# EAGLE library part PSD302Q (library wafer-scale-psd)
WAFER SCALE INTEGRATION

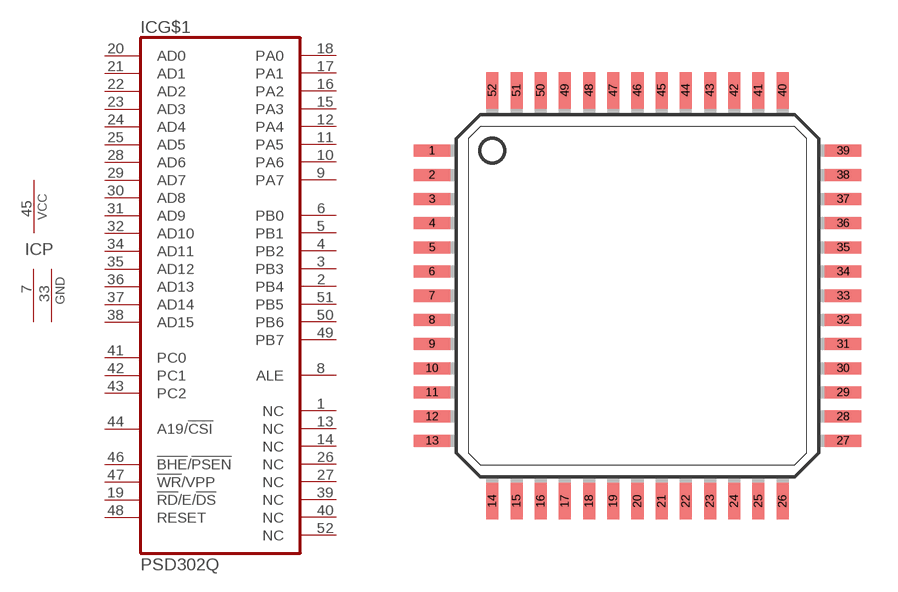
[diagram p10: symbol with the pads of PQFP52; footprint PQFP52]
Designator prefix IC; gates G$1=PSD302Q P=1VCC2GND

## PSD302Q (OC_FARNELL: unknown; OC_NEWARK: unknown)  [PQFP52]
1  G$1:NC  nc
2  G$1:PB4  out
3  G$1:PB3  out
4  G$1:PB2  out
5  G$1:PB1  out
6  G$1:PB0  out
7  P:GND  pwr
8  G$1:ALE  out
9  G$1:PA7
10  G$1:PA6
11  G$1:PA5
12  G$1:PA4
13  G$1:NC  nc
14  G$1:NC  nc
15  G$1:PA3
16  G$1:PA2
17  G$1:PA1
18  G$1:PA0
19  G$1:!RD!/E/!DS  in
20  G$1:AD0  in
21  G$1:AD1  in
22  G$1:AD2  in
23  G$1:AD3  in
24  G$1:AD4  in
25  G$1:AD5  in
26  G$1:NC  nc
27  G$1:NC  nc
28  G$1:AD6  in
29  G$1:AD7  in
30  G$1:AD8  in
31  G$1:AD9  in
32  G$1:AD10  in
33  P:GND  pwr
34  G$1:AD11  in
35  G$1:AD12  in
36  G$1:AD13  in
37  G$1:AD14  in
38  G$1:AD15  in
39  G$1:NC  nc
40  G$1:NC  nc
41  G$1:PC0  in
42  G$1:PC1  in
43  G$1:PC2  in
44  G$1:A19/!CSI  in
45  P:VCC  pwr
46  G$1:!BHE!/!PSEN  in
47  G$1:!WR!/VPP  in
48  G$1:RESET  in
49  G$1:PB7  out
50  G$1:PB6  out
51  G$1:PB5  out
52  G$1:NC  nc

## Footprint PQFP52 (pad centres in mm)
Plasic Quad Flat Package
smd 1.5 x 0.5: 1 -8.5,6; 2 -8.5,5; 3 -8.5,4; 4 -8.5,3; 5 -8.5,2; 6 -8.5,1; 7 -8.5,0; 8 -8.5,-1; 9 -8.5,-2; 10 -8.5,-3; 11 -8.5,-4; 12 -8.5,-5; 13 -8.5,-6; 27 8.5,-6; 28 8.5,-5; 29 8.5,-4; 30 8.5,-3; 31 8.5,-2; 32 8.5,-1; 33 8.5,0; 34 8.5,1; 35 8.5,2; 36 8.5,3; 37 8.5,4; 38 8.5,5; 39 8.5,6
smd 0.5 x 1.5: 14 -6,-8.5; 15 -5,-8.5; 16 -4,-8.5; 17 -3,-8.5; 18 -2,-8.5; 19 -1,-8.5; 20 0,-8.5; 21 1,-8.5; 22 2,-8.5; 23 3,-8.5; 24 4,-8.5; 25 5,-8.5; 26 6,-8.5; 40 6,8.5; 41 5,8.5; 42 4,8.5; 43 3,8.5; 44 2,8.5; 45 1,8.5; 46 0,8.5; 47 -1,8.5; 48 -2,8.5; 49 -3,8.5; 50 -4,8.5; 51 -5,8.5; 52 -6,8.5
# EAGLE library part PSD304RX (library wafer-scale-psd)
WAFER SCALE INTEGRATION

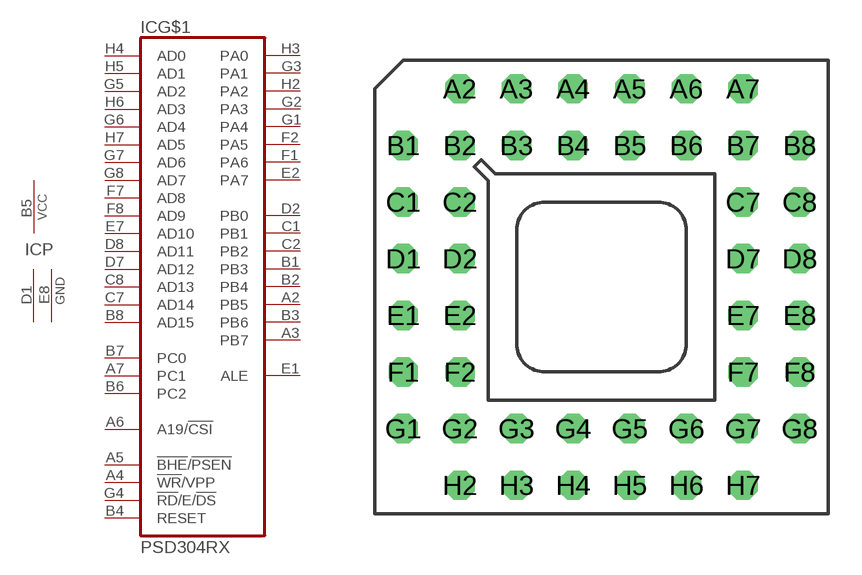
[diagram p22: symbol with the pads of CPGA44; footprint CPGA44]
Designator prefix IC; gates G$1=PSD303 P=1VCC2GND

## PSD304RX (OC_FARNELL: unknown; OC_NEWARK: unknown)  [CPGA44]
A2  G$1:PB5  out
A3  G$1:PB7  out
A4  G$1:!WR!/VPP  in
A5  G$1:!BHE!/!PSEN  in
A6  G$1:A19/!CSI  in
A7  G$1:PC1  in
B1  G$1:PB3  out
B2  G$1:PB4  out
B3  G$1:PB6  out
B4  G$1:RESET  in
B5  P:VCC  pwr
B6  G$1:PC2  in
B7  G$1:PC0  in
B8  G$1:AD15  in
C1  G$1:PB1  out
C2  G$1:PB2  out
C7  G$1:AD14  in
C8  G$1:AD13  in
D1  P:GND  pwr
D2  G$1:PB0  out
D7  G$1:AD12  in
D8  G$1:AD11  in
E1  G$1:ALE  out
E2  G$1:PA7
E7  G$1:AD10  in
E8  P:GND  pwr
F1  G$1:PA6
F2  G$1:PA5
F7  G$1:AD8  in
F8  G$1:AD9  in
G1  G$1:PA4
G2  G$1:PA3
G3  G$1:PA1
G4  G$1:!RD!/E/!DS  in
G5  G$1:AD2  in
G6  G$1:AD4  in
G7  G$1:AD6  in
G8  G$1:AD7  in
H2  G$1:PA2
H3  G$1:PA0
H4  G$1:AD0  in
H5  G$1:AD1  in
H6  G$1:AD3  in
H7  G$1:AD5  in

## Footprint CPGA44 (pad centres in mm)
Pin Grid Array
drill 0.813 octagon: A2 -6.35,8.89; A3 -3.81,8.89; A4 -1.27,8.89; A5 1.27,8.89; A6 3.81,8.89; A7 6.35,8.89; B1 -8.89,6.35; B2 -6.35,6.35; B3 -3.81,6.35; B4 -1.27,6.35; B5 1.27,6.35; B6 3.81,6.35; B7 6.35,6.35; B8 8.89,6.35; C1 -8.89,3.81; C2 -6.35,3.81; C7 6.35,3.81; C8 8.89,3.81; D1 -8.89,1.27; D2 -6.35,1.27; D7 6.35,1.27; D8 8.89,1.27; E1 -8.89,-1.27; E2 -6.35,-1.27; E7 6.35,-1.27; E8 8.89,-1.27; F1 -8.89,-3.81; F2 -6.35,-3.81; F7 6.35,-3.81; F8 8.89,-3.81; G1 -8.89,-6.35; G2 -6.35,-6.35; G3 -3.81,-6.35; G4 -1.27,-6.35; G5 1.27,-6.35; G6 3.81,-6.35; G7 6.35,-6.35; G8 8.89,-6.35; H2 -6.35,-8.89; H3 -3.81,-8.89; H4 -1.27,-8.89; H5 1.27,-8.89; H6 3.81,-8.89; H7 6.35,-8.89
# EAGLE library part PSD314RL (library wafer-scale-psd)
WAFER SCALE INTEGRATION

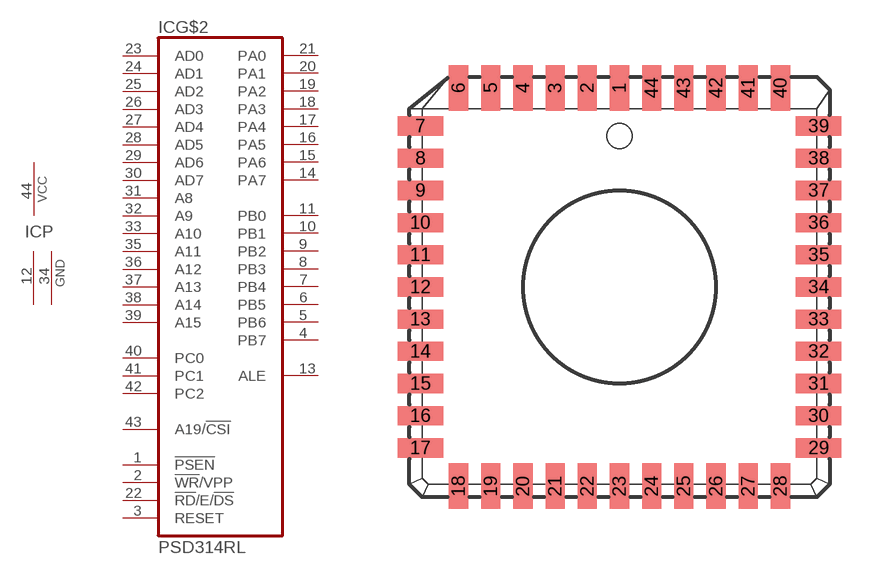
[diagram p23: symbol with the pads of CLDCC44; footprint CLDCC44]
Designator prefix IC; gates G$2=PSD312 P=1VCC2GND

## PSD314RL (OC_FARNELL: unknown; OC_NEWARK: unknown)  [CLDCC44]
1  G$2:!PSEN  in
2  G$2:!WR!/VPP  in
3  G$2:RESET  in
4  G$2:PB7  out
5  G$2:PB6  out
6  G$2:PB5  out
7  G$2:PB4  out
8  G$2:PB3  out
9  G$2:PB2  out
10  G$2:PB1  out
11  G$2:PB0  out
12  P:GND  pwr
13  G$2:ALE  out
14  G$2:PA7
15  G$2:PA6
16  G$2:PA5
17  G$2:PA4
18  G$2:PA3
19  G$2:PA2
20  G$2:PA1
21  G$2:PA0
22  G$2:!RD!/E/!DS  in
23  G$2:AD0  in
24  G$2:AD1  in
25  G$2:AD2  in
26  G$2:AD3  in
27  G$2:AD4  in
28  G$2:AD5  in
29  G$2:AD6  in
30  G$2:AD7  in
31  G$2:A8  in
32  G$2:A9  in
33  G$2:A10  in
34  P:GND  pwr
35  G$2:A11  in
36  G$2:A12  in
37  G$2:A13  in
38  G$2:A14  in
39  G$2:A15  in
40  G$2:PC0  in
41  G$2:PC1  in
42  G$2:PC2  in
43  G$2:A19/!CSI  in
44  P:VCC  pwr

## Footprint CLDCC44 (pad centres in mm)
CERAMIC LEADED CHIP CARRIER square
smd 0.76 x 1.8: 1 0,7.86; 2 -1.27,7.86; 3 -2.54,7.86; 4 -3.81,7.86; 5 -5.08,7.86; 6 -6.35,7.86; 18 -6.35,-7.86; 19 -5.08,-7.86; 20 -3.81,-7.86; 21 -2.54,-7.86; 22 -1.27,-7.86; 23 0,-7.86; 24 1.27,-7.86; 25 2.54,-7.86; 26 3.81,-7.86; 27 5.08,-7.86; 28 6.35,-7.86; 40 6.35,7.86; 41 5.08,7.86; 42 3.81,7.86; 43 2.54,7.86; 44 1.27,7.86
smd 1.8 x 0.76: 7 -7.86,6.35; 8 -7.86,5.08; 9 -7.86,3.81; 10 -7.86,2.54; 11 -7.86,1.27; 12 -7.86,0; 13 -7.86,-1.27; 14 -7.86,-2.54; 15 -7.86,-3.81; 16 -7.86,-5.08; 17 -7.86,-6.35; 29 7.86,-6.35; 30 7.86,-5.08; 31 7.86,-3.81; 32 7.86,-2.54; 33 7.86,-1.27; 34 7.86,0; 35 7.86,1.27; 36 7.86,2.54; 37 7.86,3.81; 38 7.86,5.08; 39 7.86,6.35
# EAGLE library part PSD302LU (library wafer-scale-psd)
WAFER SCALE INTEGRATION

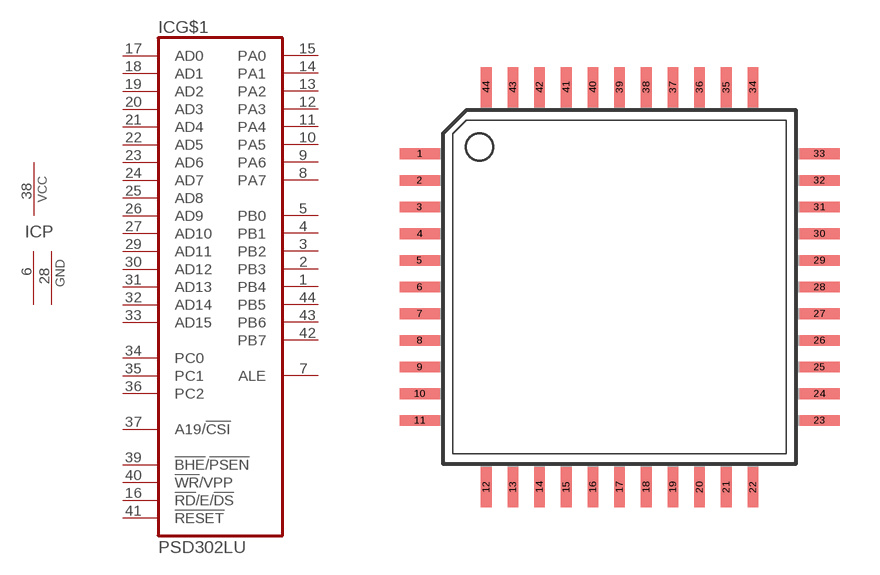
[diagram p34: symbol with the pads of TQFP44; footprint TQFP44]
Designator prefix IC; gates G$1=PSD302L P=1VCC2GND

## PSD302LU (OC_FARNELL: unknown; OC_NEWARK: unknown)  [TQFP44]
1  G$1:PB4  out
2  G$1:PB3  out
3  G$1:PB2  out
4  G$1:PB1  out
5  G$1:PB0  out
6  P:GND  pwr
7  G$1:ALE  out
8  G$1:PA7
9  G$1:PA6
10  G$1:PA5
11  G$1:PA4
12  G$1:PA3
13  G$1:PA2
14  G$1:PA1
15  G$1:PA0
16  G$1:!RD!/E/!DS  in
17  G$1:AD0  in
18  G$1:AD1  in
19  G$1:AD2  in
20  G$1:AD3  in
21  G$1:AD4  in
22  G$1:AD5  in
23  G$1:AD6  in
24  G$1:AD7  in
25  G$1:AD8  in
26  G$1:AD9  in
27  G$1:AD10  in
28  P:GND  pwr
29  G$1:AD11  in
30  G$1:AD12  in
31  G$1:AD13  in
32  G$1:AD14  in
33  G$1:AD15  in
34  G$1:PC0  in
35  G$1:PC1  in
36  G$1:PC2  in
37  G$1:A19/!CSI  in
38  P:VCC  pwr
39  G$1:!BHE!/!PSEN  in
40  G$1:!WR!/VPP  in
41  G$1:!RESET  in
42  G$1:PB7  out
43  G$1:PB6  out
44  G$1:PB5  out

## Footprint TQFP44 (pad centres in mm)
Thin Plasic Quad Flat Package 13x13mm
smd 1.5 x 0.4: 1 -7.5,5; 2 -7.5,4; 3 -7.5,3; 4 -7.5,2; 5 -7.5,1; 6 -7.5,0; 7 -7.5,-1; 8 -7.5,-2; 9 -7.5,-3; 10 -7.5,-4; 11 -7.5,-5; 23 7.5,-5; 24 7.5,-4; 25 7.5,-3; 26 7.5,-2; 27 7.5,-1; 28 7.5,0; 29 7.5,1; 30 7.5,2; 31 7.5,3; 32 7.5,4; 33 7.5,5
smd 0.4 x 1.5: 12 -5,-7.5; 13 -4,-7.5; 14 -3,-7.5; 15 -2,-7.5; 16 -1,-7.5; 17 0,-7.5; 18 1,-7.5; 19 2,-7.5; 20 3,-7.5; 21 4,-7.5; 22 5,-7.5; 34 5,7.5; 35 4,7.5; 36 3,7.5; 37 2,7.5; 38 1,7.5; 39 0,7.5; 40 -1,7.5; 41 -2,7.5; 42 -3,7.5; 43 -4,7.5; 44 -5,7.5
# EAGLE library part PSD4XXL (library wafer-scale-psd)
WAFER SCALE INTEGRATION

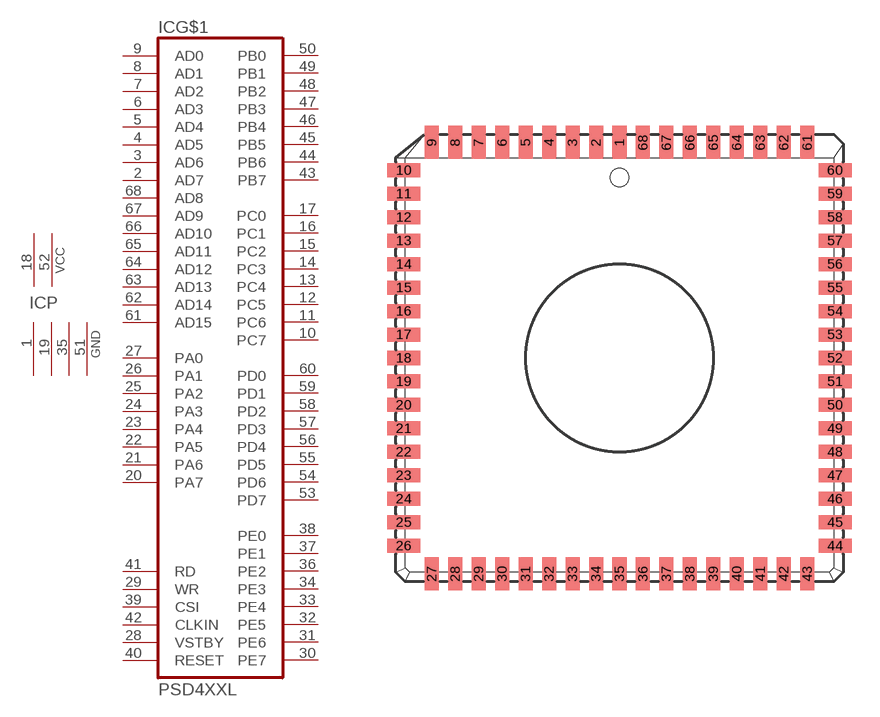
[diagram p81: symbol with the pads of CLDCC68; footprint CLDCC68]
Designator prefix IC; gates G$1=PSD4XX P=2VCC4GND

## PSD4XXL (OC_FARNELL: unknown; OC_NEWARK: unknown)  [CLDCC68]
1  P:GND  pwr
2  G$1:AD7
3  G$1:AD6
4  G$1:AD5
5  G$1:AD4
6  G$1:AD3
7  G$1:AD2
8  G$1:AD1
9  G$1:AD0
10  G$1:PC7
11  G$1:PC6
12  G$1:PC5
13  G$1:PC4
14  G$1:PC3
15  G$1:PC2
16  G$1:PC1
17  G$1:PC0
18  P:VCC  pwr
19  P:GND  pwr
20  G$1:PA7
21  G$1:PA6
22  G$1:PA5
23  G$1:PA4
24  G$1:PA3
25  G$1:PA2
26  G$1:PA1
27  G$1:PA0
28  G$1:VSTBY  in
29  G$1:WR  in
30  G$1:PE7
31  G$1:PE6
32  G$1:PE5
33  G$1:PE4
34  G$1:PE3
35  P:GND  pwr
36  G$1:PE2
37  G$1:PE1
38  G$1:PE0
39  G$1:CSI  in
40  G$1:RESET  in
41  G$1:RD  in
42  G$1:CLKIN  in
43  G$1:PB7
44  G$1:PB6
45  G$1:PB5
46  G$1:PB4
47  G$1:PB3
48  G$1:PB2
49  G$1:PB1
50  G$1:PB0
51  P:GND  pwr
52  P:VCC  pwr
53  G$1:PD7
54  G$1:PD6
55  G$1:PD5
56  G$1:PD4
57  G$1:PD3
58  G$1:PD2
59  G$1:PD1
60  G$1:PD0
61  G$1:AD15
62  G$1:AD14
63  G$1:AD13
64  G$1:AD12
65  G$1:AD11
66  G$1:AD10
67  G$1:AD9
68  G$1:AD8

## Footprint CLDCC68 (pad centres in mm)
CERAMIC LEADED CHIP CARRIER square
smd 0.76 x 1.8: 1 0,11.67; 2 -1.27,11.67; 3 -2.54,11.67; 4 -3.81,11.67; 5 -5.08,11.67; 6 -6.35,11.67; 7 -7.62,11.67; 8 -8.89,11.67; 9 -10.16,11.67; 27 -10.16,-11.67; 28 -8.89,-11.67; 29 -7.62,-11.67; 30 -6.35,-11.67; 31 -5.08,-11.67; 32 -3.81,-11.67; 33 -2.54,-11.67; 34 -1.27,-11.67; 35 0,-11.67; 36 1.27,-11.67; 37 2.54,-11.67; 38 3.81,-11.67; 39 5.08,-11.67; 40 6.35,-11.67; 41 7.62,-11.67; 42 8.89,-11.67; 43 10.16,-11.67; 61 10.16,11.67; 62 8.89,11.67; 63 7.62,11.67; 64 6.35,11.67; 65 5.08,11.67; 66 3.81,11.67; 67 2.54,11.67; 68 1.27,11.67
smd 1.8 x 0.76: 10 -11.67,10.16; 11 -11.67,8.89; 12 -11.67,7.62; 13 -11.67,6.35; 14 -11.67,5.08; 15 -11.67,3.81; 16 -11.67,2.54; 17 -11.67,1.27; 18 -11.67,0; 19 -11.67,-1.27; 20 -11.67,-2.54; 21 -11.67,-3.81; 22 -11.67,-5.08; 23 -11.67,-6.35; 24 -11.67,-7.62; 25 -11.67,-8.89; 26 -11.67,-10.16; 44 11.67,-10.16; 45 11.67,-8.89; 46 11.67,-7.62; 47 11.67,-6.35; 48 11.67,-5.08; 49 11.67,-3.81; 50 11.67,-2.54; 51 11.67,-1.27; 52 11.67,0; 53 11.67,1.27; 54 11.67,2.54; 55 11.67,3.81; 56 11.67,5.08; 57 11.67,6.35; 58 11.67,7.62; 59 11.67,8.89; 60 11.67,10.16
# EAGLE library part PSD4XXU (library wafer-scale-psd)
WAFER SCALE INTEGRATION

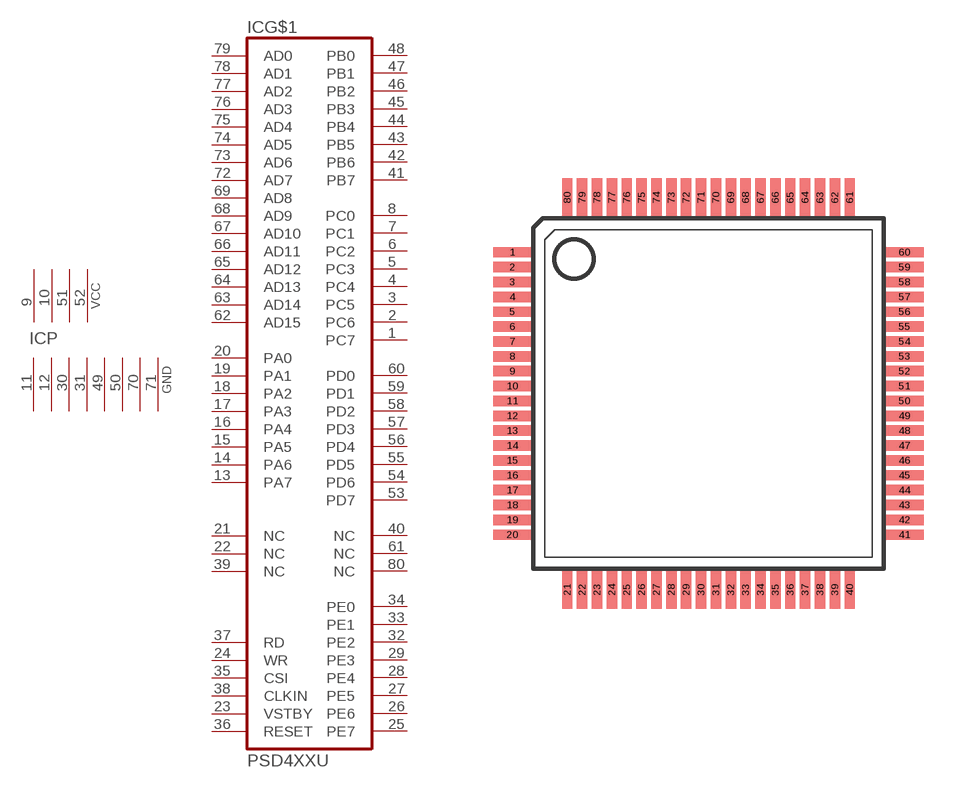
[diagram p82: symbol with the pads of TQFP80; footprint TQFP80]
Designator prefix IC; gates G$1=PSD4XXU P=4VCC8GND

## PSD4XXU (OC_FARNELL: unknown; OC_NEWARK: unknown)  [TQFP80]
1  G$1:PC7
2  G$1:PC6
3  G$1:PC5
4  G$1:PC4
5  G$1:PC3
6  G$1:PC2
7  G$1:PC1
8  G$1:PC0
9  P:VCC  pwr
10  P:VCC  pwr
11  P:GND  pwr
12  P:GND  pwr
13  G$1:PA7
14  G$1:PA6
15  G$1:PA5
16  G$1:PA4
17  G$1:PA3
18  G$1:PA2
19  G$1:PA1
20  G$1:PA0
21  G$1:NC  nc
22  G$1:NC  nc
23  G$1:VSTBY  in
24  G$1:WR  in
25  G$1:PE7
26  G$1:PE6
27  G$1:PE5
28  G$1:PE4
29  G$1:PE3
30  P:GND  pwr
31  P:GND  pwr
32  G$1:PE2
33  G$1:PE1
34  G$1:PE0
35  G$1:CSI  in
36  G$1:RESET  in
37  G$1:RD  in
38  G$1:CLKIN  in
39  G$1:NC  nc
40  G$1:NC  nc
41  G$1:PB7
42  G$1:PB6
43  G$1:PB5
44  G$1:PB4
45  G$1:PB3
46  G$1:PB2
47  G$1:PB1
48  G$1:PB0
49  P:GND  pwr
50  P:GND  pwr
51  P:VCC  pwr
52  P:VCC  pwr
53  G$1:PD7
54  G$1:PD6
55  G$1:PD5
56  G$1:PD4
57  G$1:PD3
58  G$1:PD2
59  G$1:PD1
60  G$1:PD0
61  G$1:NC  nc
62  G$1:AD15
63  G$1:AD14
64  G$1:AD13
65  G$1:AD12
66  G$1:AD11
67  G$1:AD10
68  G$1:AD9
69  G$1:AD8
70  P:GND  pwr
71  P:GND  pwr
72  G$1:AD7
73  G$1:AD6
74  G$1:AD5
75  G$1:AD4
76  G$1:AD3
77  G$1:AD2
78  G$1:AD1
79  G$1:AD0
80  G$1:NC  nc

## Footprint TQFP80 (pad centres in mm)
Thin Quad Flat Pack
smd 1.3 x 0.35: 1 -6.595,4.75; 2 -6.595,4.25; 3 -6.595,3.75; 4 -6.595,3.25; 5 -6.595,2.75; 6 -6.595,2.25; 7 -6.595,1.75; 8 -6.595,1.25; 9 -6.595,0.75; 10 -6.595,0.25; 11 -6.595,-0.25; 12 -6.595,-0.75; 13 -6.595,-1.25; 14 -6.595,-1.75; 15 -6.595,-2.25; 16 -6.595,-2.75; 17 -6.595,-3.25; 18 -6.595,-3.75; 19 -6.595,-4.25; 20 -6.595,-4.75; 41 6.595,-4.75; 42 6.595,-4.25; 43 6.595,-3.75; 44 6.595,-3.25; 45 6.595,-2.75; 46 6.595,-2.25; 47 6.595,-1.75; 48 6.595,-1.25; 49 6.595,-0.75; 50 6.595,-0.25; 51 6.595,0.25; 52 6.595,0.75; 53 6.595,1.25; 54 6.595,1.75; 55 6.595,2.25; 56 6.595,2.75; 57 6.595,3.25; 58 6.595,3.75; 59 6.595,4.25; 60 6.595,4.75
smd 0.35 x 1.3: 21 -4.75,-6.595; 22 -4.25,-6.595; 23 -3.75,-6.595; 24 -3.25,-6.595; 25 -2.75,-6.595; 26 -2.25,-6.595; 27 -1.75,-6.595; 28 -1.25,-6.595; 29 -0.75,-6.595; 30 -0.25,-6.595; 31 0.25,-6.595; 32 0.75,-6.595; 33 1.25,-6.595; 34 1.75,-6.595; 35 2.25,-6.595; 36 2.75,-6.595; 37 3.25,-6.595; 38 3.75,-6.595; 39 4.25,-6.595; 40 4.75,-6.595; 61 4.75,6.595; 62 4.25,6.595; 63 3.75,6.595; 64 3.25,6.595; 65 2.75,6.595; 66 2.25,6.595; 67 1.75,6.595; 68 1.25,6.595; 69 0.75,6.595; 70 0.25,6.595; 71 -0.25,6.595; 72 -0.75,6.595; 73 -1.25,6.595; 74 -1.75,6.595; 75 -2.25,6.595; 76 -2.75,6.595; 77 -3.25,6.595; 78 -3.75,6.595; 79 -4.25,6.595; 80 -4.75,6.595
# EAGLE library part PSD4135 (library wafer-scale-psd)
WAFER SCALE INTEGRATION

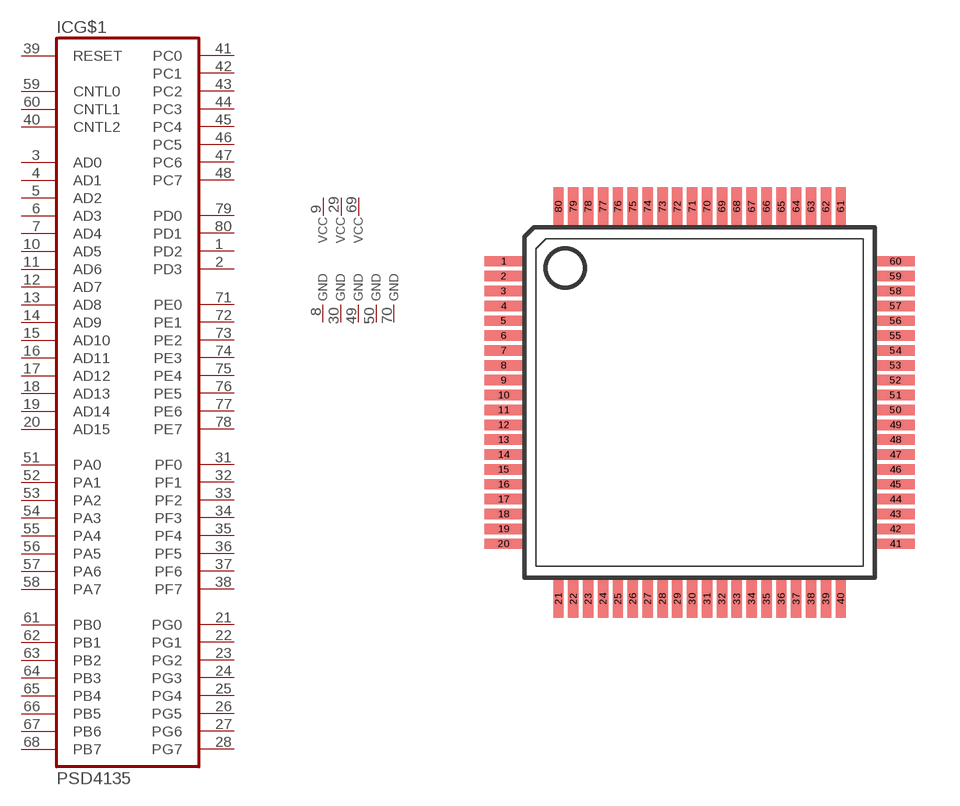
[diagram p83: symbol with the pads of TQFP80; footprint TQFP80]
Designator prefix IC; gates G$1=PSD4135 G1=GND G2=GND G3=GND G4=GND G5=GND V1=VCC V2=VCC V3=VCC

## PSD4135 (OC_FARNELL: unknown; OC_NEWARK: unknown)  [TQFP80]
1  G$1:PD2
2  G$1:PD3
3  G$1:AD0
4  G$1:AD1
5  G$1:AD2
6  G$1:AD3
7  G$1:AD4
8  G1:GNG  pwr
9  V1:VCC  pwr
10  G$1:AD5
11  G$1:AD6
12  G$1:AD7
13  G$1:AD8
14  G$1:AD9
15  G$1:AD10
16  G$1:AD11
17  G$1:AD12
18  G$1:AD13
19  G$1:AD14
20  G$1:AD15
21  G$1:PG0
22  G$1:PG1
23  G$1:PG2
24  G$1:PG3
25  G$1:PG4
26  G$1:PG5
27  G$1:PG6
28  G$1:PG7
29  V2:VCC  pwr
30  G2:GNG  pwr
31  G$1:PF0
32  G$1:PF1
33  G$1:PF2
34  G$1:PF3
35  G$1:PF4
36  G$1:PF5
37  G$1:PF6
38  G$1:PF7
39  G$1:RESET  in
40  G$1:CNTL2  in
41  G$1:PC0
42  G$1:PC1
43  G$1:PC2
44  G$1:PC3
45  G$1:PC4
46  G$1:PC5
47  G$1:PC6
48  G$1:PC7
49  G3:GNG  pwr
50  G4:GNG  pwr
51  G$1:PA0
52  G$1:PA1
53  G$1:PA2
54  G$1:PA3
55  G$1:PA4
56  G$1:PA5
57  G$1:PA6
58  G$1:PA7
59  G$1:CNTL0  in
60  G$1:CNTL1  in
61  G$1:PB0
62  G$1:PB1
63  G$1:PB2
64  G$1:PB3
65  G$1:PB4
66  G$1:PB5
67  G$1:PB6
68  G$1:PB7
69  V3:VCC  pwr
70  G5:GNG  pwr
71  G$1:PE0
72  G$1:PE1
73  G$1:PE2
74  G$1:PE3
75  G$1:PE4
76  G$1:PE5
77  G$1:PE6
78  G$1:PE7
79  G$1:PD0
80  G$1:PD1

## Footprint TQFP80 (pad centres in mm)
Thin Quad Flat Pack
smd 1.3 x 0.35: 1 -6.595,4.75; 2 -6.595,4.25; 3 -6.595,3.75; 4 -6.595,3.25; 5 -6.595,2.75; 6 -6.595,2.25; 7 -6.595,1.75; 8 -6.595,1.25; 9 -6.595,0.75; 10 -6.595,0.25; 11 -6.595,-0.25; 12 -6.595,-0.75; 13 -6.595,-1.25; 14 -6.595,-1.75; 15 -6.595,-2.25; 16 -6.595,-2.75; 17 -6.595,-3.25; 18 -6.595,-3.75; 19 -6.595,-4.25; 20 -6.595,-4.75; 41 6.595,-4.75; 42 6.595,-4.25; 43 6.595,-3.75; 44 6.595,-3.25; 45 6.595,-2.75; 46 6.595,-2.25; 47 6.595,-1.75; 48 6.595,-1.25; 49 6.595,-0.75; 50 6.595,-0.25; 51 6.595,0.25; 52 6.595,0.75; 53 6.595,1.25; 54 6.595,1.75; 55 6.595,2.25; 56 6.595,2.75; 57 6.595,3.25; 58 6.595,3.75; 59 6.595,4.25; 60 6.595,4.75
smd 0.35 x 1.3: 21 -4.75,-6.595; 22 -4.25,-6.595; 23 -3.75,-6.595; 24 -3.25,-6.595; 25 -2.75,-6.595; 26 -2.25,-6.595; 27 -1.75,-6.595; 28 -1.25,-6.595; 29 -0.75,-6.595; 30 -0.25,-6.595; 31 0.25,-6.595; 32 0.75,-6.595; 33 1.25,-6.595; 34 1.75,-6.595; 35 2.25,-6.595; 36 2.75,-6.595; 37 3.25,-6.595; 38 3.75,-6.595; 39 4.25,-6.595; 40 4.75,-6.595; 61 4.75,6.595; 62 4.25,6.595; 63 3.75,6.595; 64 3.25,6.595; 65 2.75,6.595; 66 2.25,6.595; 67 1.75,6.595; 68 1.25,6.595; 69 0.75,6.595; 70 0.25,6.595; 71 -0.25,6.595; 72 -0.75,6.595; 73 -1.25,6.595; 74 -1.75,6.595; 75 -2.25,6.595; 76 -2.75,6.595; 77 -3.25,6.595; 78 -3.75,6.595; 79 -4.25,6.595; 80 -4.75,6.595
